VERSION 5.8 ;
BUSBITCHARS "[]" ;
DIVIDERCHAR "/" ;
UNITS
    DATABASE MICRONS 2000 ;
END UNITS

VIA gemm_compute_array_via1_2_960_340_1_3_300_300
  VIARULE Via1Array-0 ;
  CUTSIZE 0.07 0.07 ;
  LAYERS metal1 via1 metal2 ;
  CUTSPACING 0.08 0.08 ;
  ENCLOSURE 0.035 0.05 0.035 0.035 ;
  ROWCOL 1 3 ;
END gemm_compute_array_via1_2_960_340_1_3_300_300

VIA gemm_compute_array_via2_3_960_340_1_3_320_320
  VIARULE Via2Array-0 ;
  CUTSIZE 0.07 0.07 ;
  LAYERS metal2 via2 metal3 ;
  CUTSPACING 0.09 0.09 ;
  ENCLOSURE 0.035 0.035 0.035 0.035 ;
  ROWCOL 1 3 ;
END gemm_compute_array_via2_3_960_340_1_3_320_320

VIA gemm_compute_array_via3_4_960_340_1_3_320_320
  VIARULE Via3Array-0 ;
  CUTSIZE 0.07 0.07 ;
  LAYERS metal3 via3 metal4 ;
  CUTSPACING 0.09 0.09 ;
  ENCLOSURE 0.035 0.035 0.045 0.035 ;
  ROWCOL 1 3 ;
END gemm_compute_array_via3_4_960_340_1_3_320_320

VIA gemm_compute_array_via4_5_960_2800_5_2_600_600
  VIARULE Via4Array-0 ;
  CUTSIZE 0.14 0.14 ;
  LAYERS metal4 via4 metal5 ;
  CUTSPACING 0.16 0.16 ;
  ENCLOSURE 0.02 0 0 0 ;
  ROWCOL 5 2 ;
END gemm_compute_array_via4_5_960_2800_5_2_600_600

VIA gemm_compute_array_via5_6_960_2800_5_2_600_600
  VIARULE Via5Array-0 ;
  CUTSIZE 0.14 0.14 ;
  LAYERS metal5 via5 metal6 ;
  CUTSPACING 0.16 0.16 ;
  ENCLOSURE 0 0 0 0 ;
  ROWCOL 5 2 ;
END gemm_compute_array_via5_6_960_2800_5_2_600_600

VIA gemm_compute_array_via6_7_960_2800_4_1_600_600
  VIARULE Via6Array-0 ;
  CUTSIZE 0.14 0.14 ;
  LAYERS metal6 via6 metal7 ;
  CUTSPACING 0.16 0.16 ;
  ENCLOSURE 0 0 0.13 0.18 ;
  ROWCOL 4 1 ;
END gemm_compute_array_via6_7_960_2800_4_1_600_600

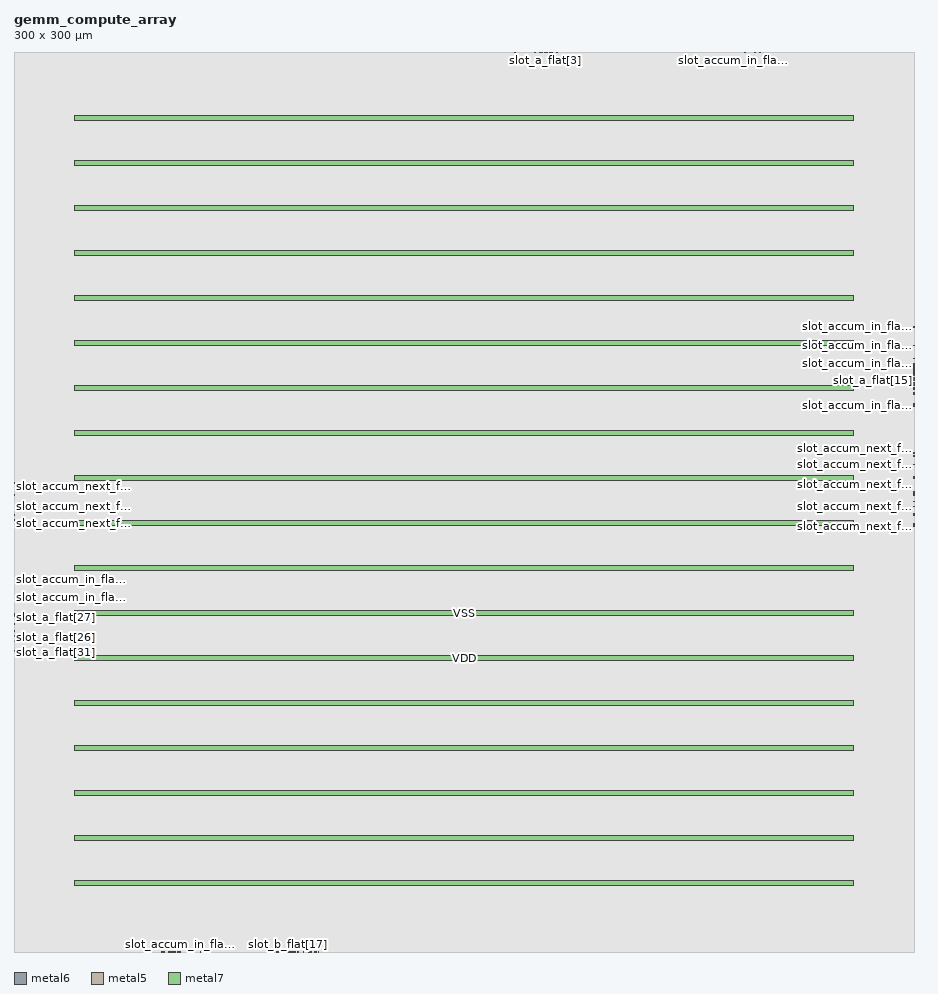
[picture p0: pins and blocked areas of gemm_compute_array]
MACRO gemm_compute_array
  FOREIGN gemm_compute_array 0 0 ;
  CLASS BLOCK ;
  SIZE 300 BY 300 ;
  PIN slot_a_flat[0]
    DIRECTION INPUT ;
    USE SIGNAL ;
    PORT
      LAYER metal6 ;
        RECT  178.105 299.86 178.245 300 ;
    END
  END slot_a_flat[0]
  PIN slot_a_flat[10]
    DIRECTION INPUT ;
    USE SIGNAL ;
    PORT
      LAYER metal5 ;
        RECT  299.86 194.32 300 194.46 ;
    END
  END slot_a_flat[10]
  PIN slot_a_flat[11]
    DIRECTION INPUT ;
    USE SIGNAL ;
    PORT
      LAYER metal5 ;
        RECT  299.86 193.76 300 193.9 ;
    END
  END slot_a_flat[11]
  PIN slot_a_flat[12]
    DIRECTION INPUT ;
    USE SIGNAL ;
    PORT
      LAYER metal5 ;
        RECT  299.86 192.64 300 192.78 ;
    END
  END slot_a_flat[12]
  PIN slot_a_flat[13]
    DIRECTION INPUT ;
    USE SIGNAL ;
    PORT
      LAYER metal5 ;
        RECT  299.86 193.2 300 193.34 ;
    END
  END slot_a_flat[13]
  PIN slot_a_flat[14]
    DIRECTION INPUT ;
    USE SIGNAL ;
    PORT
      LAYER metal5 ;
        RECT  299.86 194.88 300 195.02 ;
    END
  END slot_a_flat[14]
  PIN slot_a_flat[15]
    DIRECTION INPUT ;
    USE SIGNAL ;
    PORT
      LAYER metal5 ;
        RECT  299.86 190.4 300 190.54 ;
    END
  END slot_a_flat[15]
  PIN slot_a_flat[16]
    DIRECTION INPUT ;
    USE SIGNAL ;
    PORT
      LAYER metal6 ;
        RECT  90.745 0 90.885 0.14 ;
    END
  END slot_a_flat[16]
  PIN slot_a_flat[17]
    DIRECTION INPUT ;
    USE SIGNAL ;
    PORT
      LAYER metal6 ;
        RECT  92.425 0 92.565 0.14 ;
    END
  END slot_a_flat[17]
  PIN slot_a_flat[18]
    DIRECTION INPUT ;
    USE SIGNAL ;
    PORT
      LAYER metal6 ;
        RECT  92.985 0 93.125 0.14 ;
    END
  END slot_a_flat[18]
  PIN slot_a_flat[19]
    DIRECTION INPUT ;
    USE SIGNAL ;
    PORT
      LAYER metal6 ;
        RECT  93.545 0 93.685 0.14 ;
    END
  END slot_a_flat[19]
  PIN slot_a_flat[1]
    DIRECTION INPUT ;
    USE SIGNAL ;
    PORT
      LAYER metal6 ;
        RECT  178.665 299.86 178.805 300 ;
    END
  END slot_a_flat[1]
  PIN slot_a_flat[20]
    DIRECTION INPUT ;
    USE SIGNAL ;
    PORT
      LAYER metal6 ;
        RECT  100.825 0 100.965 0.14 ;
    END
  END slot_a_flat[20]
  PIN slot_a_flat[21]
    DIRECTION INPUT ;
    USE SIGNAL ;
    PORT
      LAYER metal6 ;
        RECT  101.385 0 101.525 0.14 ;
    END
  END slot_a_flat[21]
  PIN slot_a_flat[22]
    DIRECTION INPUT ;
    USE SIGNAL ;
    PORT
      LAYER metal6 ;
        RECT  100.265 0 100.405 0.14 ;
    END
  END slot_a_flat[22]
  PIN slot_a_flat[23]
    DIRECTION INPUT ;
    USE SIGNAL ;
    PORT
      LAYER metal6 ;
        RECT  99.145 0 99.285 0.14 ;
    END
  END slot_a_flat[23]
  PIN slot_a_flat[24]
    DIRECTION INPUT ;
    USE SIGNAL ;
    PORT
      LAYER metal6 ;
        RECT  86.825 0 86.965 0.14 ;
    END
  END slot_a_flat[24]
  PIN slot_a_flat[25]
    DIRECTION INPUT ;
    USE SIGNAL ;
    PORT
      LAYER metal6 ;
        RECT  85.705 0 85.845 0.14 ;
    END
  END slot_a_flat[25]
  PIN slot_a_flat[26]
    DIRECTION INPUT ;
    USE SIGNAL ;
    PORT
      LAYER metal5 ;
        RECT  0 104.72 0.14 104.86 ;
    END
  END slot_a_flat[26]
  PIN slot_a_flat[27]
    DIRECTION INPUT ;
    USE SIGNAL ;
    PORT
      LAYER metal5 ;
        RECT  0 111.44 0.14 111.58 ;
    END
  END slot_a_flat[27]
  PIN slot_a_flat[28]
    DIRECTION INPUT ;
    USE SIGNAL ;
    PORT
      LAYER metal5 ;
        RECT  0 112.56 0.14 112.7 ;
    END
  END slot_a_flat[28]
  PIN slot_a_flat[29]
    DIRECTION INPUT ;
    USE SIGNAL ;
    PORT
      LAYER metal5 ;
        RECT  0 106.96 0.14 107.1 ;
    END
  END slot_a_flat[29]
  PIN slot_a_flat[2]
    DIRECTION INPUT ;
    USE SIGNAL ;
    PORT
      LAYER metal6 ;
        RECT  177.545 299.86 177.685 300 ;
    END
  END slot_a_flat[2]
  PIN slot_a_flat[30]
    DIRECTION INPUT ;
    USE SIGNAL ;
    PORT
      LAYER metal5 ;
        RECT  0 104.16 0.14 104.3 ;
    END
  END slot_a_flat[30]
  PIN slot_a_flat[31]
    DIRECTION INPUT ;
    USE SIGNAL ;
    PORT
      LAYER metal5 ;
        RECT  0 99.68 0.14 99.82 ;
    END
  END slot_a_flat[31]
  PIN slot_a_flat[3]
    DIRECTION INPUT ;
    USE SIGNAL ;
    PORT
      LAYER metal6 ;
        RECT  176.985 299.86 177.125 300 ;
    END
  END slot_a_flat[3]
  PIN slot_a_flat[4]
    DIRECTION INPUT ;
    USE SIGNAL ;
    PORT
      LAYER metal6 ;
        RECT  174.745 299.86 174.885 300 ;
    END
  END slot_a_flat[4]
  PIN slot_a_flat[5]
    DIRECTION INPUT ;
    USE SIGNAL ;
    PORT
      LAYER metal6 ;
        RECT  167.465 299.86 167.605 300 ;
    END
  END slot_a_flat[5]
  PIN slot_a_flat[6]
    DIRECTION INPUT ;
    USE SIGNAL ;
    PORT
      LAYER metal6 ;
        RECT  166.345 299.86 166.485 300 ;
    END
  END slot_a_flat[6]
  PIN slot_a_flat[7]
    DIRECTION INPUT ;
    USE SIGNAL ;
    PORT
      LAYER metal6 ;
        RECT  166.905 299.86 167.045 300 ;
    END
  END slot_a_flat[7]
  PIN slot_a_flat[8]
    DIRECTION INPUT ;
    USE SIGNAL ;
    PORT
      LAYER metal6 ;
        RECT  168.025 299.86 168.165 300 ;
    END
  END slot_a_flat[8]
  PIN slot_a_flat[9]
    DIRECTION INPUT ;
    USE SIGNAL ;
    PORT
      LAYER metal6 ;
        RECT  165.785 299.86 165.925 300 ;
    END
  END slot_a_flat[9]
  PIN slot_accum_in_flat[0]
    DIRECTION INPUT ;
    USE SIGNAL ;
    PORT
      LAYER metal6 ;
        RECT  248.665 299.86 248.805 300 ;
    END
  END slot_accum_in_flat[0]
  PIN slot_accum_in_flat[10]
    DIRECTION INPUT ;
    USE SIGNAL ;
    PORT
      LAYER metal5 ;
        RECT  299.86 185.92 300 186.06 ;
    END
  END slot_accum_in_flat[10]
  PIN slot_accum_in_flat[11]
    DIRECTION INPUT ;
    USE SIGNAL ;
    PORT
      LAYER metal5 ;
        RECT  299.86 182 300 182.14 ;
    END
  END slot_accum_in_flat[11]
  PIN slot_accum_in_flat[12]
    DIRECTION INPUT ;
    USE SIGNAL ;
    PORT
      LAYER metal5 ;
        RECT  299.86 182.56 300 182.7 ;
    END
  END slot_accum_in_flat[12]
  PIN slot_accum_in_flat[13]
    DIRECTION INPUT ;
    USE SIGNAL ;
    PORT
      LAYER metal5 ;
        RECT  299.86 188.72 300 188.86 ;
    END
  END slot_accum_in_flat[13]
  PIN slot_accum_in_flat[14]
    DIRECTION INPUT ;
    USE SIGNAL ;
    PORT
      LAYER metal5 ;
        RECT  299.86 186.48 300 186.62 ;
    END
  END slot_accum_in_flat[14]
  PIN slot_accum_in_flat[15]
    DIRECTION INPUT ;
    USE SIGNAL ;
    PORT
      LAYER metal5 ;
        RECT  299.86 191.52 300 191.66 ;
    END
  END slot_accum_in_flat[15]
  PIN slot_accum_in_flat[16]
    DIRECTION INPUT ;
    USE SIGNAL ;
    PORT
      LAYER metal6 ;
        RECT  49.865 0 50.005 0.14 ;
    END
  END slot_accum_in_flat[16]
  PIN slot_accum_in_flat[17]
    DIRECTION INPUT ;
    USE SIGNAL ;
    PORT
      LAYER metal6 ;
        RECT  52.665 0 52.805 0.14 ;
    END
  END slot_accum_in_flat[17]
  PIN slot_accum_in_flat[18]
    DIRECTION INPUT ;
    USE SIGNAL ;
    PORT
      LAYER metal6 ;
        RECT  49.305 0 49.445 0.14 ;
    END
  END slot_accum_in_flat[18]
  PIN slot_accum_in_flat[19]
    DIRECTION INPUT ;
    USE SIGNAL ;
    PORT
      LAYER metal6 ;
        RECT  53.785 0 53.925 0.14 ;
    END
  END slot_accum_in_flat[19]
  PIN slot_accum_in_flat[1]
    DIRECTION INPUT ;
    USE SIGNAL ;
    PORT
      LAYER metal6 ;
        RECT  248.105 299.86 248.245 300 ;
    END
  END slot_accum_in_flat[1]
  PIN slot_accum_in_flat[20]
    DIRECTION INPUT ;
    USE SIGNAL ;
    PORT
      LAYER metal6 ;
        RECT  55.465 0 55.605 0.14 ;
    END
  END slot_accum_in_flat[20]
  PIN slot_accum_in_flat[21]
    DIRECTION INPUT ;
    USE SIGNAL ;
    PORT
      LAYER metal6 ;
        RECT  52.105 0 52.245 0.14 ;
    END
  END slot_accum_in_flat[21]
  PIN slot_accum_in_flat[22]
    DIRECTION INPUT ;
    USE SIGNAL ;
    PORT
      LAYER metal6 ;
        RECT  53.225 0 53.365 0.14 ;
    END
  END slot_accum_in_flat[22]
  PIN slot_accum_in_flat[23]
    DIRECTION INPUT ;
    USE SIGNAL ;
    PORT
      LAYER metal6 ;
        RECT  54.345 0 54.485 0.14 ;
    END
  END slot_accum_in_flat[23]
  PIN slot_accum_in_flat[24]
    DIRECTION INPUT ;
    USE SIGNAL ;
    PORT
      LAYER metal6 ;
        RECT  54.905 0 55.045 0.14 ;
    END
  END slot_accum_in_flat[24]
  PIN slot_accum_in_flat[25]
    DIRECTION INPUT ;
    USE SIGNAL ;
    PORT
      LAYER metal6 ;
        RECT  51.545 0 51.685 0.14 ;
    END
  END slot_accum_in_flat[25]
  PIN slot_accum_in_flat[26]
    DIRECTION INPUT ;
    USE SIGNAL ;
    PORT
      LAYER metal5 ;
        RECT  0 115.36 0.14 115.5 ;
    END
  END slot_accum_in_flat[26]
  PIN slot_accum_in_flat[27]
    DIRECTION INPUT ;
    USE SIGNAL ;
    PORT
      LAYER metal5 ;
        RECT  0 118.72 0.14 118.86 ;
    END
  END slot_accum_in_flat[27]
  PIN slot_accum_in_flat[28]
    DIRECTION INPUT ;
    USE SIGNAL ;
    PORT
      LAYER metal5 ;
        RECT  0 117.04 0.14 117.18 ;
    END
  END slot_accum_in_flat[28]
  PIN slot_accum_in_flat[29]
    DIRECTION INPUT ;
    USE SIGNAL ;
    PORT
      LAYER metal5 ;
        RECT  0 121.52 0.14 121.66 ;
    END
  END slot_accum_in_flat[29]
  PIN slot_accum_in_flat[2]
    DIRECTION INPUT ;
    USE SIGNAL ;
    PORT
      LAYER metal6 ;
        RECT  239.705 299.86 239.845 300 ;
    END
  END slot_accum_in_flat[2]
  PIN slot_accum_in_flat[30]
    DIRECTION INPUT ;
    USE SIGNAL ;
    PORT
      LAYER metal5 ;
        RECT  0 120.4 0.14 120.54 ;
    END
  END slot_accum_in_flat[30]
  PIN slot_accum_in_flat[31]
    DIRECTION INPUT ;
    USE SIGNAL ;
    PORT
      LAYER metal5 ;
        RECT  0 100.8 0.14 100.94 ;
    END
  END slot_accum_in_flat[31]
  PIN slot_accum_in_flat[3]
    DIRECTION INPUT ;
    USE SIGNAL ;
    PORT
      LAYER metal6 ;
        RECT  243.625 299.86 243.765 300 ;
    END
  END slot_accum_in_flat[3]
  PIN slot_accum_in_flat[4]
    DIRECTION INPUT ;
    USE SIGNAL ;
    PORT
      LAYER metal5 ;
        RECT  299.86 208.32 300 208.46 ;
    END
  END slot_accum_in_flat[4]
  PIN slot_accum_in_flat[5]
    DIRECTION INPUT ;
    USE SIGNAL ;
    PORT
      LAYER metal6 ;
        RECT  246.985 299.86 247.125 300 ;
    END
  END slot_accum_in_flat[5]
  PIN slot_accum_in_flat[6]
    DIRECTION INPUT ;
    USE SIGNAL ;
    PORT
      LAYER metal6 ;
        RECT  251.465 299.86 251.605 300 ;
    END
  END slot_accum_in_flat[6]
  PIN slot_accum_in_flat[7]
    DIRECTION INPUT ;
    USE SIGNAL ;
    PORT
      LAYER metal5 ;
        RECT  299.86 202.16 300 202.3 ;
    END
  END slot_accum_in_flat[7]
  PIN slot_accum_in_flat[8]
    DIRECTION INPUT ;
    USE SIGNAL ;
    PORT
      LAYER metal5 ;
        RECT  299.86 196 300 196.14 ;
    END
  END slot_accum_in_flat[8]
  PIN slot_accum_in_flat[9]
    DIRECTION INPUT ;
    USE SIGNAL ;
    PORT
      LAYER metal5 ;
        RECT  299.86 197.68 300 197.82 ;
    END
  END slot_accum_in_flat[9]
  PIN slot_accum_next_flat[0]
    DIRECTION OUTPUT ;
    USE SIGNAL ;
    PORT
      LAYER metal5 ;
        RECT  299.86 141.68 300 141.82 ;
    END
  END slot_accum_next_flat[0]
  PIN slot_accum_next_flat[10]
    DIRECTION OUTPUT ;
    USE SIGNAL ;
    PORT
      LAYER metal5 ;
        RECT  299.86 162.4 300 162.54 ;
    END
  END slot_accum_next_flat[10]
  PIN slot_accum_next_flat[11]
    DIRECTION OUTPUT ;
    USE SIGNAL ;
    PORT
      LAYER metal5 ;
        RECT  299.86 158.48 300 158.62 ;
    END
  END slot_accum_next_flat[11]
  PIN slot_accum_next_flat[12]
    DIRECTION OUTPUT ;
    USE SIGNAL ;
    PORT
      LAYER metal5 ;
        RECT  299.86 157.92 300 158.06 ;
    END
  END slot_accum_next_flat[12]
  PIN slot_accum_next_flat[13]
    DIRECTION OUTPUT ;
    USE SIGNAL ;
    PORT
      LAYER metal5 ;
        RECT  299.86 165.2 300 165.34 ;
    END
  END slot_accum_next_flat[13]
  PIN slot_accum_next_flat[14]
    DIRECTION OUTPUT ;
    USE SIGNAL ;
    PORT
      LAYER metal5 ;
        RECT  299.86 166.32 300 166.46 ;
    END
  END slot_accum_next_flat[14]
  PIN slot_accum_next_flat[15]
    DIRECTION OUTPUT ;
    USE SIGNAL ;
    PORT
      LAYER metal5 ;
        RECT  299.86 187.6 300 187.74 ;
    END
  END slot_accum_next_flat[15]
  PIN slot_accum_next_flat[16]
    DIRECTION OUTPUT ;
    USE SIGNAL ;
    PORT
      LAYER metal5 ;
        RECT  0 155.12 0.14 155.26 ;
    END
  END slot_accum_next_flat[16]
  PIN slot_accum_next_flat[17]
    DIRECTION OUTPUT ;
    USE SIGNAL ;
    PORT
      LAYER metal5 ;
        RECT  0 155.68 0.14 155.82 ;
    END
  END slot_accum_next_flat[17]
  PIN slot_accum_next_flat[18]
    DIRECTION OUTPUT ;
    USE SIGNAL ;
    PORT
      LAYER metal5 ;
        RECT  0 156.24 0.14 156.38 ;
    END
  END slot_accum_next_flat[18]
  PIN slot_accum_next_flat[19]
    DIRECTION OUTPUT ;
    USE SIGNAL ;
    PORT
      LAYER metal5 ;
        RECT  0 152.32 0.14 152.46 ;
    END
  END slot_accum_next_flat[19]
  PIN slot_accum_next_flat[1]
    DIRECTION OUTPUT ;
    USE SIGNAL ;
    PORT
      LAYER metal5 ;
        RECT  299.86 142.24 300 142.38 ;
    END
  END slot_accum_next_flat[1]
  PIN slot_accum_next_flat[20]
    DIRECTION OUTPUT ;
    USE SIGNAL ;
    PORT
      LAYER metal5 ;
        RECT  0 148.4 0.14 148.54 ;
    END
  END slot_accum_next_flat[20]
  PIN slot_accum_next_flat[21]
    DIRECTION OUTPUT ;
    USE SIGNAL ;
    PORT
      LAYER metal5 ;
        RECT  0 149.52 0.14 149.66 ;
    END
  END slot_accum_next_flat[21]
  PIN slot_accum_next_flat[22]
    DIRECTION OUTPUT ;
    USE SIGNAL ;
    PORT
      LAYER metal5 ;
        RECT  0 146.16 0.14 146.3 ;
    END
  END slot_accum_next_flat[22]
  PIN slot_accum_next_flat[23]
    DIRECTION OUTPUT ;
    USE SIGNAL ;
    PORT
      LAYER metal5 ;
        RECT  0 145.6 0.14 145.74 ;
    END
  END slot_accum_next_flat[23]
  PIN slot_accum_next_flat[24]
    DIRECTION OUTPUT ;
    USE SIGNAL ;
    PORT
      LAYER metal5 ;
        RECT  0 142.8 0.14 142.94 ;
    END
  END slot_accum_next_flat[24]
  PIN slot_accum_next_flat[25]
    DIRECTION OUTPUT ;
    USE SIGNAL ;
    PORT
      LAYER metal5 ;
        RECT  0 143.36 0.14 143.5 ;
    END
  END slot_accum_next_flat[25]
  PIN slot_accum_next_flat[26]
    DIRECTION OUTPUT ;
    USE SIGNAL ;
    PORT
      LAYER metal5 ;
        RECT  0 144.48 0.14 144.62 ;
    END
  END slot_accum_next_flat[26]
  PIN slot_accum_next_flat[27]
    DIRECTION OUTPUT ;
    USE SIGNAL ;
    PORT
      LAYER metal5 ;
        RECT  0 145.04 0.14 145.18 ;
    END
  END slot_accum_next_flat[27]
  PIN slot_accum_next_flat[28]
    DIRECTION OUTPUT ;
    USE SIGNAL ;
    PORT
      LAYER metal5 ;
        RECT  0 141.68 0.14 141.82 ;
    END
  END slot_accum_next_flat[28]
  PIN slot_accum_next_flat[29]
    DIRECTION OUTPUT ;
    USE SIGNAL ;
    PORT
      LAYER metal5 ;
        RECT  0 143.92 0.14 144.06 ;
    END
  END slot_accum_next_flat[29]
  PIN slot_accum_next_flat[2]
    DIRECTION OUTPUT ;
    USE SIGNAL ;
    PORT
      LAYER metal5 ;
        RECT  299.86 142.8 300 142.94 ;
    END
  END slot_accum_next_flat[2]
  PIN slot_accum_next_flat[30]
    DIRECTION OUTPUT ;
    USE SIGNAL ;
    PORT
      LAYER metal5 ;
        RECT  0 141.12 0.14 141.26 ;
    END
  END slot_accum_next_flat[30]
  PIN slot_accum_next_flat[31]
    DIRECTION OUTPUT ;
    USE SIGNAL ;
    PORT
      LAYER metal5 ;
        RECT  0 103.6 0.14 103.74 ;
    END
  END slot_accum_next_flat[31]
  PIN slot_accum_next_flat[3]
    DIRECTION OUTPUT ;
    USE SIGNAL ;
    PORT
      LAYER metal5 ;
        RECT  299.86 145.6 300 145.74 ;
    END
  END slot_accum_next_flat[3]
  PIN slot_accum_next_flat[4]
    DIRECTION OUTPUT ;
    USE SIGNAL ;
    PORT
      LAYER metal5 ;
        RECT  299.86 146.16 300 146.3 ;
    END
  END slot_accum_next_flat[4]
  PIN slot_accum_next_flat[5]
    DIRECTION OUTPUT ;
    USE SIGNAL ;
    PORT
      LAYER metal5 ;
        RECT  299.86 148.4 300 148.54 ;
    END
  END slot_accum_next_flat[5]
  PIN slot_accum_next_flat[6]
    DIRECTION OUTPUT ;
    USE SIGNAL ;
    PORT
      LAYER metal5 ;
        RECT  299.86 150.08 300 150.22 ;
    END
  END slot_accum_next_flat[6]
  PIN slot_accum_next_flat[7]
    DIRECTION OUTPUT ;
    USE SIGNAL ;
    PORT
      LAYER metal5 ;
        RECT  299.86 152.88 300 153.02 ;
    END
  END slot_accum_next_flat[7]
  PIN slot_accum_next_flat[8]
    DIRECTION OUTPUT ;
    USE SIGNAL ;
    PORT
      LAYER metal5 ;
        RECT  299.86 153.44 300 153.58 ;
    END
  END slot_accum_next_flat[8]
  PIN slot_accum_next_flat[9]
    DIRECTION OUTPUT ;
    USE SIGNAL ;
    PORT
      LAYER metal5 ;
        RECT  299.86 152.32 300 152.46 ;
    END
  END slot_accum_next_flat[9]
  PIN slot_b_flat[0]
    DIRECTION INPUT ;
    USE SIGNAL ;
    PORT
      LAYER metal6 ;
        RECT  179.225 299.86 179.365 300 ;
    END
  END slot_b_flat[0]
  PIN slot_b_flat[10]
    DIRECTION INPUT ;
    USE SIGNAL ;
    PORT
      LAYER metal5 ;
        RECT  299.86 189.28 300 189.42 ;
    END
  END slot_b_flat[10]
  PIN slot_b_flat[11]
    DIRECTION INPUT ;
    USE SIGNAL ;
    PORT
      LAYER metal5 ;
        RECT  299.86 188.16 300 188.3 ;
    END
  END slot_b_flat[11]
  PIN slot_b_flat[12]
    DIRECTION INPUT ;
    USE SIGNAL ;
    PORT
      LAYER metal5 ;
        RECT  299.86 190.96 300 191.1 ;
    END
  END slot_b_flat[12]
  PIN slot_b_flat[13]
    DIRECTION INPUT ;
    USE SIGNAL ;
    PORT
      LAYER metal5 ;
        RECT  299.86 192.08 300 192.22 ;
    END
  END slot_b_flat[13]
  PIN slot_b_flat[14]
    DIRECTION INPUT ;
    USE SIGNAL ;
    PORT
      LAYER metal5 ;
        RECT  299.86 195.44 300 195.58 ;
    END
  END slot_b_flat[14]
  PIN slot_b_flat[15]
    DIRECTION INPUT ;
    USE SIGNAL ;
    PORT
      LAYER metal5 ;
        RECT  299.86 189.84 300 189.98 ;
    END
  END slot_b_flat[15]
  PIN slot_b_flat[16]
    DIRECTION INPUT ;
    USE SIGNAL ;
    PORT
      LAYER metal6 ;
        RECT  90.185 0 90.325 0.14 ;
    END
  END slot_b_flat[16]
  PIN slot_b_flat[17]
    DIRECTION INPUT ;
    USE SIGNAL ;
    PORT
      LAYER metal6 ;
        RECT  91.305 0 91.445 0.14 ;
    END
  END slot_b_flat[17]
  PIN slot_b_flat[18]
    DIRECTION INPUT ;
    USE SIGNAL ;
    PORT
      LAYER metal6 ;
        RECT  91.865 0 92.005 0.14 ;
    END
  END slot_b_flat[18]
  PIN slot_b_flat[19]
    DIRECTION INPUT ;
    USE SIGNAL ;
    PORT
      LAYER metal6 ;
        RECT  87.385 0 87.525 0.14 ;
    END
  END slot_b_flat[19]
  PIN slot_b_flat[1]
    DIRECTION INPUT ;
    USE SIGNAL ;
    PORT
      LAYER metal6 ;
        RECT  181.465 299.86 181.605 300 ;
    END
  END slot_b_flat[1]
  PIN slot_b_flat[20]
    DIRECTION INPUT ;
    USE SIGNAL ;
    PORT
      LAYER metal6 ;
        RECT  98.025 0 98.165 0.14 ;
    END
  END slot_b_flat[20]
  PIN slot_b_flat[21]
    DIRECTION INPUT ;
    USE SIGNAL ;
    PORT
      LAYER metal6 ;
        RECT  98.585 0 98.725 0.14 ;
    END
  END slot_b_flat[21]
  PIN slot_b_flat[22]
    DIRECTION INPUT ;
    USE SIGNAL ;
    PORT
      LAYER metal6 ;
        RECT  96.345 0 96.485 0.14 ;
    END
  END slot_b_flat[22]
  PIN slot_b_flat[23]
    DIRECTION INPUT ;
    USE SIGNAL ;
    PORT
      LAYER metal6 ;
        RECT  94.665 0 94.805 0.14 ;
    END
  END slot_b_flat[23]
  PIN slot_b_flat[24]
    DIRECTION INPUT ;
    USE SIGNAL ;
    PORT
      LAYER metal6 ;
        RECT  62.185 0 62.325 0.14 ;
    END
  END slot_b_flat[24]
  PIN slot_b_flat[25]
    DIRECTION INPUT ;
    USE SIGNAL ;
    PORT
      LAYER metal6 ;
        RECT  87.945 0 88.085 0.14 ;
    END
  END slot_b_flat[25]
  PIN slot_b_flat[26]
    DIRECTION INPUT ;
    USE SIGNAL ;
    PORT
      LAYER metal5 ;
        RECT  0 105.84 0.14 105.98 ;
    END
  END slot_b_flat[26]
  PIN slot_b_flat[27]
    DIRECTION INPUT ;
    USE SIGNAL ;
    PORT
      LAYER metal5 ;
        RECT  0 109.2 0.14 109.34 ;
    END
  END slot_b_flat[27]
  PIN slot_b_flat[28]
    DIRECTION INPUT ;
    USE SIGNAL ;
    PORT
      LAYER metal5 ;
        RECT  0 112 0.14 112.14 ;
    END
  END slot_b_flat[28]
  PIN slot_b_flat[29]
    DIRECTION INPUT ;
    USE SIGNAL ;
    PORT
      LAYER metal5 ;
        RECT  0 107.52 0.14 107.66 ;
    END
  END slot_b_flat[29]
  PIN slot_b_flat[2]
    DIRECTION INPUT ;
    USE SIGNAL ;
    PORT
      LAYER metal6 ;
        RECT  180.905 299.86 181.045 300 ;
    END
  END slot_b_flat[2]
  PIN slot_b_flat[30]
    DIRECTION INPUT ;
    USE SIGNAL ;
    PORT
      LAYER metal5 ;
        RECT  0 105.28 0.14 105.42 ;
    END
  END slot_b_flat[30]
  PIN slot_b_flat[31]
    DIRECTION INPUT ;
    USE SIGNAL ;
    PORT
      LAYER metal5 ;
        RECT  0 100.24 0.14 100.38 ;
    END
  END slot_b_flat[31]
  PIN slot_b_flat[3]
    DIRECTION INPUT ;
    USE SIGNAL ;
    PORT
      LAYER metal6 ;
        RECT  172.505 299.86 172.645 300 ;
    END
  END slot_b_flat[3]
  PIN slot_b_flat[4]
    DIRECTION INPUT ;
    USE SIGNAL ;
    PORT
      LAYER metal6 ;
        RECT  175.305 299.86 175.445 300 ;
    END
  END slot_b_flat[4]
  PIN slot_b_flat[5]
    DIRECTION INPUT ;
    USE SIGNAL ;
    PORT
      LAYER metal6 ;
        RECT  173.065 299.86 173.205 300 ;
    END
  END slot_b_flat[5]
  PIN slot_b_flat[6]
    DIRECTION INPUT ;
    USE SIGNAL ;
    PORT
      LAYER metal6 ;
        RECT  173.625 299.86 173.765 300 ;
    END
  END slot_b_flat[6]
  PIN slot_b_flat[7]
    DIRECTION INPUT ;
    USE SIGNAL ;
    PORT
      LAYER metal6 ;
        RECT  174.185 299.86 174.325 300 ;
    END
  END slot_b_flat[7]
  PIN slot_b_flat[8]
    DIRECTION INPUT ;
    USE SIGNAL ;
    PORT
      LAYER metal6 ;
        RECT  175.865 299.86 176.005 300 ;
    END
  END slot_b_flat[8]
  PIN slot_b_flat[9]
    DIRECTION INPUT ;
    USE SIGNAL ;
    PORT
      LAYER metal6 ;
        RECT  176.425 299.86 176.565 300 ;
    END
  END slot_b_flat[9]
  PIN VSS
    DIRECTION INOUT ;
    USE GROUND ;
    PORT
      LAYER metal7 ;
        RECT  20.14 262.3 279.87 263.7 ;
        RECT  20.14 232.3 279.87 233.7 ;
        RECT  20.14 202.3 279.87 203.7 ;
        RECT  20.14 172.3 279.87 173.7 ;
        RECT  20.14 142.3 279.87 143.7 ;
        RECT  20.14 112.3 279.87 113.7 ;
        RECT  20.14 82.3 279.87 83.7 ;
        RECT  20.14 52.3 279.87 53.7 ;
        RECT  20.14 22.3 279.87 23.7 ;
    END
  END VSS
  PIN VDD
    DIRECTION INOUT ;
    USE POWER ;
    PORT
      LAYER metal7 ;
        RECT  20.14 277.3 279.87 278.7 ;
        RECT  20.14 247.3 279.87 248.7 ;
        RECT  20.14 217.3 279.87 218.7 ;
        RECT  20.14 187.3 279.87 188.7 ;
        RECT  20.14 157.3 279.87 158.7 ;
        RECT  20.14 127.3 279.87 128.7 ;
        RECT  20.14 97.3 279.87 98.7 ;
        RECT  20.14 67.3 279.87 68.7 ;
        RECT  20.14 37.3 279.87 38.7 ;
    END
  END VDD
  OBS
    LAYER metal1 ;
     RECT  0 0 300 300 ;
    LAYER metal2 ;
     RECT  0 0 300 300 ;
    LAYER metal3 ;
     RECT  0 0 300 300 ;
    LAYER metal4 ;
     RECT  0 0 300 300 ;
    LAYER metal5 ;
     RECT  0 0 300 300 ;
    LAYER metal6 ;
     RECT  0 0 300 300 ;
    LAYER metal7 ;
     RECT  0 0 300 300 ;
    LAYER metal8 ;
     RECT  0 0 300 300 ;
    LAYER metal9 ;
     RECT  0 0 300 300 ;
  END
END gemm_compute_array
END LIBRARY
